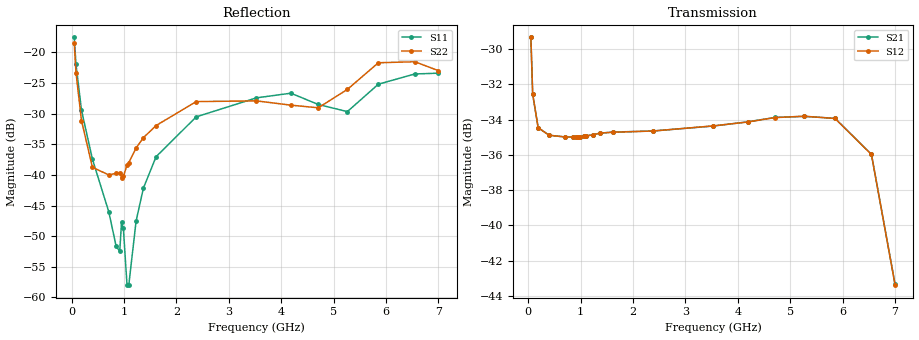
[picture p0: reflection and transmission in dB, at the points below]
! Integrated Device Technology
! Corporate Headquarters
! 6024 Silver Creek Valley Road
! San Jose, CA 95138  USA
! Phone:  1-408-284-8200
! Toll Free:  1-800-223-1366
! Webpage:  http://www.idt.com/
! Timing and RF Division
! 515 Groton Road, Suite 102
! Westford, MA 01886-6024
! Device:  F2258
! Description: Voltage Variable RF Attenuator
! Frequency:  50.0 -  6000.00 MHz
! Package:  3x3 mm Thin QFN Plastic Package: 16 pin
! Ports:  2 RF, 2 DC
!  Pin  1  = NC
!  Pin  2  = NC
!  Pin  3  = RF2  = Port 2
!  Pin  4  = GND
!  Pin  5  = Vdd
!  Pin  6  = NC
!  Pin  7  = VCTRL
!  Pin  8  = NC
!  Pin  9  = GND
!  Pin 10  = RF1  = Port 1
!  Pin 11  = NC
!  Pin 12  = NC
!  Pin 13  = NC
!  Pin 14  = NC
!  Pin 15  = NC
!  Pin 16  = NC
! Vcntrl:  2.000 Volts
! Vdd:  +3.300 Volts
! Current:  1.153 mA
! Data:  The device was measured on a the F2258 evaluation board which has
!  individual transmission lines to the RF pins.  Data was collected
!  using a calibrated network analyzer.  The evaluation board was
!  de-embedded using a TRL calibration technique.
!  The reference plane is the edge of the package pin.
! Misc:  SN 10
!  Action Tracker AT0285
! Date Measured:  2014-12-10
! Date:  2016-01-13  MJV
! Note:
!  Integrated Device Technology supplies this data as a sample of measured
!  data at the package pin for this product.  Your particular data for this
!  product may vary.
!  Data was taken at 25 degrees C.
!  Integrated Device Technology reserves the right to change this data at anytime.
!Freq_(GHz)  S11M_(dB)  S11P_(deg)  S21M_(dB)  S21P_(deg)  S12M_(dB)  S12P_(deg)  S22M_(dB)  S22P_(deg)
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# GHz S dB R 50
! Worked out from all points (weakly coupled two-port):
!   201 points, 50 MHz to 7 GHz, reference 50 ohm
!   highest |S21| = -29.34 dB at 50 MHz (marker M1); lowest = -43.3 dB at 7 GHz (marker M2)
!   lowest |S11| = -58.0 dB at 1.058 GHz (marker M3), VSWR 1.00, Z = 49.9 + j0.058 ohm
!   |S11| at or under -10 dB: start of sweep to end of sweep
!   |S22| runs from -40.5 to -18.5 dB; largest |S21 - S12| = 7.8e-05
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0.05  -17.55 -110.9  -29.34 -66.6  -29.34 -66.6  -18.49 -108.0
0.08475  -21.97 -107.3  -32.56 -47.1  -32.56 -47.1  -23.35 -99.0
0.189  -29.41 -109.3  -34.46 -23.9  -34.46 -23.9  -31.12 -84.5
0.3975  -37.42 -119.1  -34.89 -13.0  -34.89 -13.0  -38.75 -48.2
0.71025  -46.03 -136.4  -34.99 -9.3  -34.99 -9.3  -40.00 6.7
0.84925  -51.61 -173.8  -34.99 -8.7  -34.99 -8.7  -39.73 17.1
0.91875  -52.47 150.7  -34.98 -8.6  -34.98 -8.6  -39.64 19.3
0.9535  -47.73 -162.6  -34.99 -8.5  -34.99 -8.5  -40.49 38.2
0.98825  -48.73 -173.6  -34.97 -8.4  -34.97 -8.4  -40.25 34.9
1.05775  -57.98 152.6  -34.95 -8.3  -34.95 -8.3  -38.41 32.0
1.0925  -57.89 118.5  -34.93 -8.3  -34.93 -8.3  -37.97 31.6
1.2315  -47.49 45.3  -34.87 -8.4  -34.87 -8.4  -35.60 27.5
1.3705  -42.13 36.7  -34.77 -8.9  -34.77 -8.9  -33.92 26.2
1.61375  -37.01 32.6  -34.71 -10.2  -34.72 -10.2  -31.93 23.2
2.37825  -30.52 47.9  -34.65 -14.0  -34.65 -14.0  -28.03 24.6
3.525  -27.42 91.6  -34.37 -20.8  -34.36 -20.8  -27.91 51.5
4.18525  -26.66 104.9  -34.13 -25.5  -34.14 -25.5  -28.61 61.3
4.7065  -28.50 95.6  -33.88 -30.1  -33.89 -30.1  -29.04 43.2
5.2625  -29.66 54.3  -33.82 -36.3  -33.81 -36.2  -26.04 7.3
5.85325  -25.19 29.8  -33.93 -46.6  -33.94 -46.6  -21.69 -10.9
6.54825  -23.52 45.0  -35.97 -66.7  -35.98 -66.7  -21.52 -44.6
7  -23.39 84.4  -43.35 -62.6  -43.39 -62.1  -22.98 -127.8
